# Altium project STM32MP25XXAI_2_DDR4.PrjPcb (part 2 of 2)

## Sheet 2_DDR4_16bits.SchDoc: 2_DDR4_16bits
size A3; Date: Not used; ApprovedBy: Not used; CheckedBy: Not used; Author: Not used; CompanyName: STMicroelectronics; DrawnBy: Not used; Engineer: Not used; Organization: Not used; Address1: Not used; Address2: Not used; Address3: Not used; Address4: Not used; DocumentNumber: 6; Revision: Not used; SheetNumber: 6; SheetTotal: 7

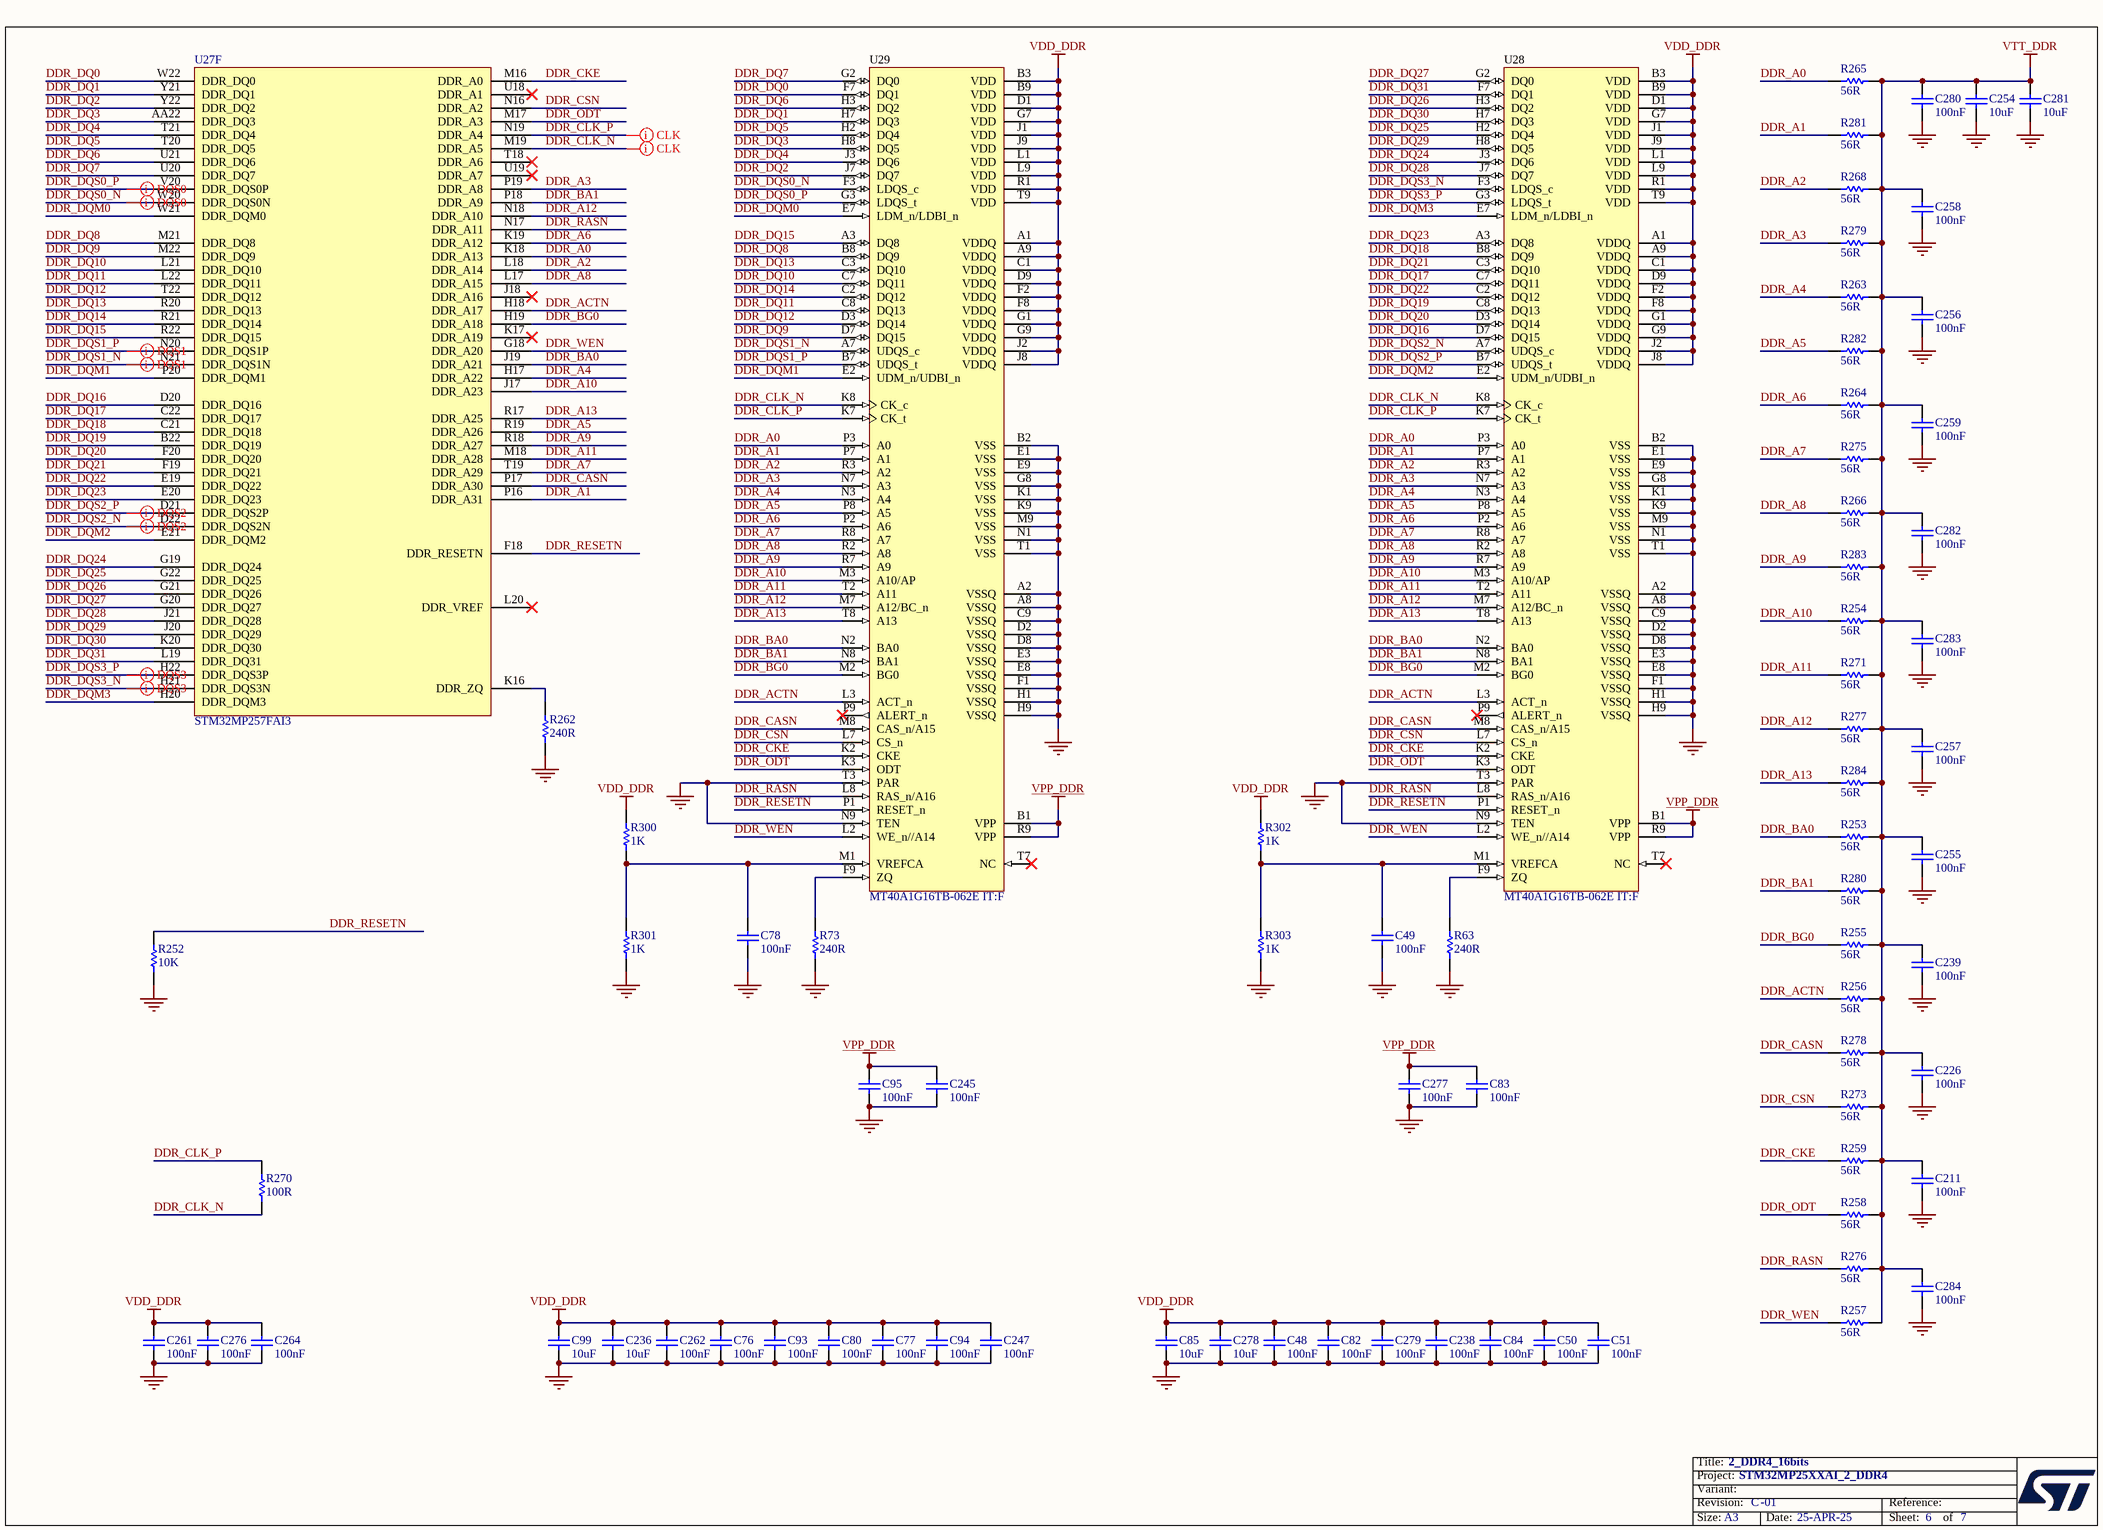
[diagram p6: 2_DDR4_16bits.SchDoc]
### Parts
C48  value 100nF  [C0402]  (hidden comment: Capacitor)
C49  value 100nF  [C0402]  (hidden comment: Capacitor)
C50  value 100nF  [C0402]  (hidden comment: Capacitor)
C51  value 100nF  [C0402]  (hidden comment: Capacitor)
C76  value 100nF  [C0402]  (hidden comment: Capacitor)
C77  value 100nF  [C0402]  (hidden comment: Capacitor)
C78  value 100nF  [C0402]  (hidden comment: Capacitor)
C80  value 100nF  [C0402]  (hidden comment: Capacitor)
C82  value 100nF  [C0402]  (hidden comment: Capacitor)
C83  value 100nF  [C0402]  (hidden comment: Capacitor)
C84  value 100nF  [C0402]  (hidden comment: Capacitor)
C85  value 10uF  [C0603]  (hidden comment: Capacitor)
C93  value 100nF  [C0402]  (hidden comment: Capacitor)
C94  value 100nF  [C0402]  (hidden comment: Capacitor)
C95  value 100nF  [C0402]  (hidden comment: Capacitor)
C99  value 10uF  [C0603]  (hidden comment: Capacitor)
C211  value 100nF  [C0402]  (hidden comment: Capacitor)
C226  value 100nF  [C0402]  (hidden comment: Capacitor)
C236  value 10uF  [C0603]  (hidden comment: Capacitor)
C238  value 100nF  [C0402]  (hidden comment: Capacitor)
C239  value 100nF  [C0402]  (hidden comment: Capacitor)
C245  value 100nF  [C0402]  (hidden comment: Capacitor)
C247  value 100nF  [C0402]  (hidden comment: Capacitor)
C254  value 10uF  [C0603]  (hidden comment: Capacitor)
C255  value 100nF  [C0402]  (hidden comment: Capacitor)
C256  value 100nF  [C0402]  (hidden comment: Capacitor)
C257  value 100nF  [C0402]  (hidden comment: Capacitor)
C258  value 100nF  [C0402]  (hidden comment: Capacitor)
C259  value 100nF  [C0402]  (hidden comment: Capacitor)
C261  value 100nF  [C0402]  (hidden comment: Capacitor)
C262  value 100nF  [C0402]  (hidden comment: Capacitor)
C264  value 100nF  [C0402]  (hidden comment: Capacitor)
C276  value 100nF  [C0402]  (hidden comment: Capacitor)
C277  value 100nF  [C0402]  (hidden comment: Capacitor)
C278  value 10uF  [C0603]  (hidden comment: Capacitor)
C279  value 100nF  [C0402]  (hidden comment: Capacitor)
C280  value 100nF  [C0402]  (hidden comment: Capacitor)
C281  value 10uF  [C0603]  (hidden comment: Capacitor)
C282  value 100nF  [C0402]  (hidden comment: Capacitor)
C283  value 100nF  [C0402]  (hidden comment: Capacitor)
C284  value 100nF  [C0402]  (hidden comment: Capacitor)
R63  value 240R  [R0201_H0P23]  (hidden comment: Resistor)
R73  value 240R  [R0201_H0P23]  (hidden comment: Resistor)
R252  value 10K  [R0402]  (hidden comment: Resistor)
R253  value 56R  [R0402]  (hidden comment: Resistor)
R254  value 56R  [R0402]  (hidden comment: Resistor)
R255  value 56R  [R0402]  (hidden comment: Resistor)
R256  value 56R  [R0402]  (hidden comment: Resistor)
R257  value 56R  [R0402]  (hidden comment: Resistor)
R258  value 56R  [R0402]  (hidden comment: Resistor)
R259  value 56R  [R0402]  (hidden comment: Resistor)
R262  value 240R  [R0201_H0P23]  (hidden comment: Resistor)
R263  value 56R  [R0402]  (hidden comment: Resistor)
R264  value 56R  [R0402]  (hidden comment: Resistor)
R265  value 56R  [R0402]  (hidden comment: Resistor)
R266  value 56R  [R0402]  (hidden comment: Resistor)
R268  value 56R  [R0402]  (hidden comment: Resistor)
R270  value 100R  [R0402]  (hidden comment: Resistor)
R271  value 56R  [R0402]  (hidden comment: Resistor)
R273  value 56R  [R0402]  (hidden comment: Resistor)
R275  value 56R  [R0402]  (hidden comment: Resistor)
R276  value 56R  [R0402]  (hidden comment: Resistor)
R277  value 56R  [R0402]  (hidden comment: Resistor)
R278  value 56R  [R0402]  (hidden comment: Resistor)
R279  value 56R  [R0402]  (hidden comment: Resistor)
R280  value 56R  [R0402]  (hidden comment: Resistor)
R281  value 56R  [R0402]  (hidden comment: Resistor)
R282  value 56R  [R0402]  (hidden comment: Resistor)
R283  value 56R  [R0402]  (hidden comment: Resistor)
R284  value 56R  [R0402]  (hidden comment: Resistor)
R300  value 1K  [R0402]  (hidden comment: Resistor)
R301  value 1K  [R0402]  (hidden comment: Resistor)
R302  value 1K  [R0402]  (hidden comment: Resistor)
R303  value 1K  [R0402]  (hidden comment: Resistor)
U27  STM32MP257FAI3  [ICC_LFBGA436_18X18_P080_H1P70_STM32MP257_CODE-B0D1]  (part F of 9)
U28  MT40A1G16TB-062E IT:F  [ICC_FBGA96_TB_7P5X13_P080]
U29  MT40A1G16TB-062E IT:F  [ICC_FBGA96_TB_7P5X13_P080]

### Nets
GND: C48.1 C49.1 C50.1 C51.1 C76.1 C77.1 C78.1 C80.1 C82.1 C83.1 C84.1 C85.1 C93.1 C94.1 C95.1 C99.1 C211.1 C226.1 C236.1 C238.1 C239.1 C245.1 C247.1 C254.1 C255.1 C256.1 C257.1 C258.1 C259.1 C261.1 C262.1 C264.1 C276.1 C277.1 C278.1 C279.1 C280.1 C281.1 C282.1 C283.1 C284.1 R63.1 R73.1 R252.1 R262.1 R301.1 R303.1 U28.A2(VSSQ) U28.A8(VSSQ) U28.B2(VSS) U28.C9(VSSQ) U28.D2(VSSQ) U28.D8(VSSQ) U28.E1(VSS) U28.E3(VSSQ) U28.E8(VSSQ) U28.E9(VSS) U28.F1(VSSQ) U28.G8(VSS) U28.H1(VSSQ) U28.H9(VSSQ) U28.K1(VSS) U28.K9(VSS) U28.M9(VSS) U28.N1(VSS) U28.N9(TEN) U28.T1(VSS) U28.T3(PAR) U29.A2(VSSQ) U29.A8(VSSQ) U29.B2(VSS) U29.C9(VSSQ) U29.D2(VSSQ) U29.D8(VSSQ) U29.E1(VSS) U29.E3(VSSQ) U29.E8(VSSQ) U29.E9(VSS) U29.F1(VSSQ) U29.G8(VSS) U29.H1(VSSQ) U29.H9(VSSQ) U29.K1(VSS) U29.K9(VSS) U29.M9(VSS) U29.N1(VSS) U29.N9(TEN) U29.T1(VSS) U29.T3(PAR)
VDD_DDR: C48.2 C50.2 C51.2 C76.2 C77.2 C80.2 C82.2 C84.2 C85.2 C93.2 C94.2 C99.2 C236.2 C238.2 C247.2 C261.2 C262.2 C264.2 C276.2 C278.2 C279.2 R300.2 R302.2 U28.A1(VDDQ) U28.A9(VDDQ) U28.B3(VDD) U28.B9(VDD) U28.C1(VDDQ) U28.D1(VDD) U28.D9(VDDQ) U28.F2(VDDQ) U28.F8(VDDQ) U28.G1(VDDQ) U28.G7(VDD) U28.G9(VDDQ) U28.J1(VDD) U28.J2(VDDQ) U28.J8(VDDQ) U28.J9(VDD) U28.L1(VDD) U28.L9(VDD) U28.R1(VDD) U28.T9(VDD) U29.A1(VDDQ) U29.A9(VDDQ) U29.B3(VDD) U29.B9(VDD) U29.C1(VDDQ) U29.D1(VDD) U29.D9(VDDQ) U29.F2(VDDQ) U29.F8(VDDQ) U29.G1(VDDQ) U29.G7(VDD) U29.G9(VDDQ) U29.J1(VDD) U29.J2(VDDQ) U29.J8(VDDQ) U29.J9(VDD) U29.L1(VDD) U29.L9(VDD) U29.R1(VDD) U29.T9(VDD)
VPP_DDR: C83.2 C95.2 C245.2 C277.2 U28.B1(VPP) U28.R9(VPP) U29.B1(VPP) U29.R9(VPP)
VTT_DDR: C211.2 C226.2 C239.2 C254.2 C255.2 C256.2 C257.2 C258.2 C259.2 C280.2 C281.2 C282.2 C283.2 C284.2 R253.2 R254.2 R255.2 R256.2 R257.2 R258.2 R259.2 R263.2 R264.2 R265.2 R266.2 R268.2 R271.2 R273.2 R275.2 R276.2 R277.2 R278.2 R279.2 R280.2 R281.2 R282.2 R283.2 R284.2
DDR_A0: R265.1 U27.K18(DDR_A13) U28.P3(A0) U29.P3(A0)
DDR_A1: R281.1 U27.P16(DDR_A31) U28.P7(A1) U29.P7(A1)
DDR_A2: R268.1 U27.L18(DDR_A14) U28.R3(A2) U29.R3(A2)
DDR_A3: R279.1 U27.P19(DDR_A8) U28.N7(A3) U29.N7(A3)
DDR_A4: R263.1 U27.H17(DDR_A22) U28.N3(A4) U29.N3(A4)
DDR_A5: R282.1 U27.R19(DDR_A26) U28.P8(A5) U29.P8(A5)
DDR_A6: R264.1 U27.K19(DDR_A12) U28.P2(A6) U29.P2(A6)
DDR_A7: R275.1 U27.T19(DDR_A29) U28.R8(A7) U29.R8(A7)
DDR_A8: R266.1 U27.L17(DDR_A15) U28.R2(A8) U29.R2(A8)
DDR_A9: R283.1 U27.R18(DDR_A27) U28.R7(A9) U29.R7(A9)
DDR_A10: R254.1 U27.J17(DDR_A23) U28.M3(A10/AP) U29.M3(A10/AP)
DDR_A11: R271.1 U27.M18(DDR_A28) U28.T2(A11) U29.T2(A11)
DDR_A12: R277.1 U27.N18(DDR_A10) U28.M7(A12/BC_n) U29.M7(A12/BC_n)
DDR_A13: R284.1 U27.R17(DDR_A25) U28.T8(A13) U29.T8(A13)
DDR_ACTN: R256.1 U27.H18(DDR_A17) U28.L3(ACT_n) U29.L3(ACT_n)
DDR_BA0: R253.1 U27.J19(DDR_A21) U28.N2(BA0) U29.N2(BA0)
DDR_BA1: R280.1 U27.P18(DDR_A9) U28.N8(BA1) U29.N8(BA1)
DDR_BG0: R255.1 U27.H19(DDR_A18) U28.M2(BG0) U29.M2(BG0)
DDR_CASN: R278.1 U27.P17(DDR_A30) U28.M8(CAS_n/A15) U29.M8(CAS_n/A15)
DDR_CKE: R259.1 U27.M16(DDR_A0) U28.K2(CKE) U29.K2(CKE)
DDR_CLK_N: R270.2 U27.M19(DDR_A5) U28.K8(CK_c) U29.K8(CK_c)
DDR_CLK_P: R270.1 U27.N19(DDR_A4) U28.K7(CK_t) U29.K7(CK_t)
DDR_CSN: R273.1 U27.N16(DDR_A2) U28.L7(CS_n) U29.L7(CS_n)
DDR_DQ0: U27.W22(DDR_DQ0) U29.F7(DQ1)
DDR_DQ1: U27.Y21(DDR_DQ1) U29.H7(DQ3)
DDR_DQ2: U27.Y22(DDR_DQ2) U29.J7(DQ7)
DDR_DQ3: U27.AA22(DDR_DQ3) U29.H8(DQ5)
DDR_DQ4: U27.T21(DDR_DQ4) U29.J3(DQ6)
DDR_DQ5: U27.T20(DDR_DQ5) U29.H2(DQ4)
DDR_DQ6: U27.U21(DDR_DQ6) U29.H3(DQ2)
DDR_DQ7: U27.U20(DDR_DQ7) U29.G2(DQ0)
DDR_DQ8: U27.M21(DDR_DQ8) U29.B8(DQ9)
DDR_DQ9: U27.M22(DDR_DQ9) U29.D7(DQ15)
DDR_DQ10: U27.L21(DDR_DQ10) U29.C7(DQ11)
DDR_DQ11: U27.L22(DDR_DQ11) U29.C8(DQ13)
DDR_DQ12: U27.T22(DDR_DQ12) U29.D3(DQ14)
DDR_DQ13: U27.R20(DDR_DQ13) U29.C3(DQ10)
DDR_DQ14: U27.R21(DDR_DQ14) U29.C2(DQ12)
DDR_DQ15: U27.R22(DDR_DQ15) U29.A3(DQ8)
DDR_DQ16: U27.D20(DDR_DQ16) U28.D7(DQ15)
DDR_DQ17: U27.C22(DDR_DQ17) U28.C7(DQ11)
DDR_DQ18: U27.C21(DDR_DQ18) U28.B8(DQ9)
DDR_DQ19: U27.B22(DDR_DQ19) U28.C8(DQ13)
DDR_DQ20: U27.F20(DDR_DQ20) U28.D3(DQ14)
DDR_DQ21: U27.F19(DDR_DQ21) U28.C3(DQ10)
DDR_DQ22: U27.E19(DDR_DQ22) U28.C2(DQ12)
DDR_DQ23: U27.E20(DDR_DQ23) U28.A3(DQ8)
DDR_DQ24: U27.G19(DDR_DQ24) U28.J3(DQ6)
DDR_DQ25: U27.G22(DDR_DQ25) U28.H2(DQ4)
DDR_DQ26: U27.G21(DDR_DQ26) U28.H3(DQ2)
DDR_DQ27: U27.G20(DDR_DQ27) U28.G2(DQ0)
DDR_DQ28: U27.J21(DDR_DQ28) U28.J7(DQ7)
DDR_DQ29: U27.J20(DDR_DQ29) U28.H8(DQ5)
DDR_DQ30: U27.K20(DDR_DQ30) U28.H7(DQ3)
DDR_DQ31: U27.L19(DDR_DQ31) U28.F7(DQ1)
DDR_DQM0: U27.W21(DDR_DQM0) U29.E7(LDM_n/LDBI_n)
DDR_DQM1: U27.P20(DDR_DQM1) U29.E2(UDM_n/UDBI_n)
DDR_DQM2: U27.E21(DDR_DQM2) U28.E2(UDM_n/UDBI_n)
DDR_DQM3: U27.H20(DDR_DQM3) U28.E7(LDM_n/LDBI_n)
DDR_DQS0_N: U27.W20(DDR_DQS0N) U29.F3(LDQS_c)
DDR_DQS0_P: U27.V20(DDR_DQS0P) U29.G3(LDQS_t)
DDR_DQS1_N: U27.N21(DDR_DQS1N) U29.A7(UDQS_c)
DDR_DQS1_P: U27.N20(DDR_DQS1P) U29.B7(UDQS_t)
DDR_DQS2_N: U27.D22(DDR_DQS2N) U28.A7(UDQS_c)
DDR_DQS2_P: U27.D21(DDR_DQS2P) U28.B7(UDQS_t)
DDR_DQS3_N: U27.H21(DDR_DQS3N) U28.F3(LDQS_c)
DDR_DQS3_P: U27.H22(DDR_DQS3P) U28.G3(LDQS_t)
DDR_ODT: R258.1 U27.M17(DDR_A3) U28.K3(ODT) U29.K3(ODT)
DDR_RASN: R276.1 U27.N17(DDR_A11) U28.L8(RAS_n/A16) U29.L8(RAS_n/A16)
DDR_RESETN: R252.2 U27.F18(DDR_RESETN) U28.P1(RESET_n) U29.P1(RESET_n)
DDR_WEN: R257.1 U27.G18(DDR_A20) U28.L2(WE_n//A14) U29.L2(WE_n//A14)
NetC49_2: C49.2 R302.1 R303.2 U28.M1(VREFCA)
NetC78_2: C78.2 R300.1 R301.2 U29.M1(VREFCA)
NetR63_2: R63.2 U28.F9(ZQ)
NetR73_2: R73.2 U29.F9(ZQ)
NetR262_2: R262.2 U27.K16(DDR_ZQ)

Not connected (* = marked no-connect by the designer): U27 J18(DDR_A16)* K17(DDR_A19)* L20(DDR_VREF)* T18(DDR_A6)* U18(DDR_A1)* U19(DDR_A7)*; U28 P9(ALERT_n)* T7(NC)*; U29 P9(ALERT_n)* T7(NC)*

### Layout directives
differential pair: DDR_CLK_N, DDR_CLK_P, DDR_DQS0_N, DDR_DQS0_P, DDR_DQS1_N, DDR_DQS1_P, DDR_DQS2_N, DDR_DQS2_P, DDR_DQS3_N, DDR_DQS3_P

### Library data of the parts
C48-C51 C76-C78 C80 C82-C84 C93-C95 C211 C226 C238 C239 C245 C247 C255-C259 C261 C262 C264 C276 C277 C279 C280 C282-C284 = MCD-00006: Capacitor, MLCC, 100nF, 16V, X7R, +/-10%, 0402, T=0.5mm; Part_Preference: Recommended; Manufacturer: YAGEO; Manufacturer_Part_Number: CC0402KRX7R7BB104; Alternate_Manufacturer: MURATA; Alternate_Manufacturer_Part_Number: GCM155R71C104KA55D; Partial_Alternate_Internal_Part_Number: MCD-03299; Order_Code_RS: 9402047; Component_Country_Of_Origin: China; ID: 2474; ShowFields: YES
C85 C99 C236 C278 = MCD-01341: Capacitor, MLCC, 10uF, 6V3, X5R, +/-20%, 0603, T=0,8mm; Part_Preference: Recommended; Manufacturer: MURATA; Manufacturer_Part_Number: GRM188R60J106ME47D; Alternate_Manufacturer_Part_Number: GRM188R60J106ME84D; Component_Country_Of_Origin: Japan°°; ID: 3441; ShowFields: YES
C254 C281 = MCD-00099: Capacitor, MLCC, 10uF, 10V, X5R, +/-10%, 0603, T=0.8mm; Part_Preference: Recommended; Manufacturer: MURATA; Manufacturer_Part_Number: GRM188R61A106KE69D; Partial_Alternate_Internal_Part_Number: MCD-03152; Order_Code_RS: 2494233; Component_Country_Of_Origin: Japan°°; ShowFields: YES; ID: 2770
R63 R73 R262 = MCD-02253: Resistor,240R,0201,1%,1/20W; Part_Preference: Recommended; Manufacturer: YAGEO; Manufacturer_Part_Number: RC0201FR-07240RL; Component_Country_Of_Origin: China; ID: 4353; ShowFields: YES
R252 = MCD-00053: Resistor,10K,0402,1%,1/16W; BMS_Part_Number: 9131590; Part_Preference: Recommended; Manufacturer: YAGEO; Manufacturer_Part_Number: RC0402FR-0710KL; Order_Code_RS: 9239359; Component_Country_Of_Origin: China; ID: 2539; ShowFields: YES
R253-R259 R263-R266 R268 R271 R273 R275-R284 = MCD-00054: Resistor, 56R, 0402, +/-1%, 1/16W; Part_Preference: Recommended; Manufacturer: YAGEO; Manufacturer_Part_Number: RC0402FR-0756RL; Order_Code_RS: 9239081; Component_Country_Of_Origin: China; ID: 2538; ShowFields: YES
R270 = MCD-01819: Resistor,100R,0402,0,5%,1/16W,±100ppm/°C; Part_Preference: Recommended; Manufacturer: YAGEO; Manufacturer_Part_Number: RC0402DR-07100RL; Component_Country_Of_Origin: China; ID: 3919; ShowFields: YES
R300-R303 = MCD-00061: Resistor, 1K, 0402, +/-1%,1/16W; Part_Preference: Recommended; Manufacturer: YAGEO; Manufacturer_Part_Number: RC0402FR-071KL; Order_Code_RS: 9239235; Component_Country_Of_Origin: China; ShowFields: YES; ID: 2532
U27 = MCD-02000: MPU, ARM Cortex-A35 + M33 32-bit MPU, 808KB RAM, With Crypto; Part_Type: IC; Part_Preference: Recommended; Manufacturer: STMICROELECTRONICS; Manufacturer_HQ_COO: EU; Component_Country_Of_Origin: Unknown; ShowFields: YES; ID: 4100
U28 = MCD-03523: Memory, DDR4 SDRAM, 1V2, 16Gbit, FBGA96; Part_Type: IC; Part_Preference: Not recommended; Manufacturer: MICRON; Component_Country_Of_Origin: Taiwan°; ShowFields: YES; ID: 5639
U29 = MCD-03523: Memory, DDR4 SDRAM, 1V2, 16Gbit, 1.6 GHz, FBGA96; Part_Type: IC; Part_Preference: Not recommended; Manufacturer: MICRON; Component_Country_Of_Origin: Taiwan°; ShowFields: YES; ID: 5639

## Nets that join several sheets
1V8: PMIC (5 pins), STM32MP25XXAI Power (20 pins), eMMC (11 pins)
GND: STM32MP25XXAI I_Os (7 pins), PMIC (62 pins), STM32MP25XXAI Power (104 pins), eMMC (17 pins), 2_DDR4_16bits (89 pins)
VDD3V3_USB: PMIC (C156.2 U26.13), STM32MP25XXAI Power (R286.1)
VDD_DDR: PMIC (7 pins), STM32MP25XXAI Power (16 pins), 2_DDR4_16bits (63 pins)
VDD_EMMC: PMIC (C190.1 U26.16), eMMC (6 pins)
VDDA1V8_AON: STM32MP25XXAI I_Os (U27.T7), PMIC (C189.2 U26.14), STM32MP25XXAI Power (C234.2 U27.R7)
VDDCORE: PMIC (6 pins), STM32MP25XXAI Power (20 pins)
VDDCPU: PMIC (5 pins), STM32MP25XXAI Power (14 pins)
VDDGPU: PMIC (6 pins), STM32MP25XXAI Power (12 pins)
VDDIO: STM32MP25XXAI I_Os (R27.2 R260.2 R261.2), PMIC (6 pins), STM32MP25XXAI Power (18 pins)
VDDIO_SDCARD: PMIC (C217.1 U26.2), STM32MP25XXAI Power (C71.2 U27.G10)
VPP_DDR: PMIC (C91.1 U26.7), 2_DDR4_16bits (8 pins)
VTT_DDR: PMIC (C40.2 U26.44), 2_DDR4_16bits (38 pins)
eMMC.SDMMC2_CK: STM32MP25XXAI I_Os (U27.A20), eMMC (R49.1 U24.M6)
eMMC.SDMMC2_CMD: STM32MP25XXAI I_Os (U27.F17), eMMC (R37.1 U24.M5)
eMMC.SDMMC2_D0: STM32MP25XXAI I_Os (U27.B19), eMMC (R44.1 U24.A3)
eMMC.SDMMC2_D1: STM32MP25XXAI I_Os (U27.E17), eMMC (U24.A4)
eMMC.SDMMC2_D2: STM32MP25XXAI I_Os (U27.C18), eMMC (U24.A5)
eMMC.SDMMC2_D3: STM32MP25XXAI I_Os (U27.C19), eMMC (U24.B2)
eMMC.SDMMC2_D4: STM32MP25XXAI I_Os (U27.A19), eMMC (U24.B3)
eMMC.SDMMC2_D5: STM32MP25XXAI I_Os (U27.D18), eMMC (U24.B4)
eMMC.SDMMC2_D6: STM32MP25XXAI I_Os (U27.E16), eMMC (U24.B5)
eMMC.SDMMC2_D7: STM32MP25XXAI I_Os (U27.D17), eMMC (U24.B6)
I2C7.SCL: STM32MP25XXAI I_Os (R261.1 U27.F16), PMIC (U26.33)
I2C7.SDA: STM32MP25XXAI I_Os (R260.1 U27.G15), PMIC (U26.34)
MP257_WAKEUP: STM32MP25XXAI I_Os (U27.Y2), PMIC (U26.32)
NRST: STM32MP25XXAI I_Os (C33.2 U27.U3), PMIC (R81.1)
NRSTC1MS: STM32MP25XXAI I_Os (R27.1 R272.1 U27.T3), PMIC (R59.1), eMMC (D5.2)
PMIC_WAKEUPn: STM32MP25XXAI I_Os (U27.P6), PMIC (R46.1)
PWR_CPU_ON: STM32MP25XXAI I_Os (R272.2 U27.T6), PMIC (R60.1)
PWR_ON: STM32MP25XXAI I_Os (U27.T5), PMIC (R2.1)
